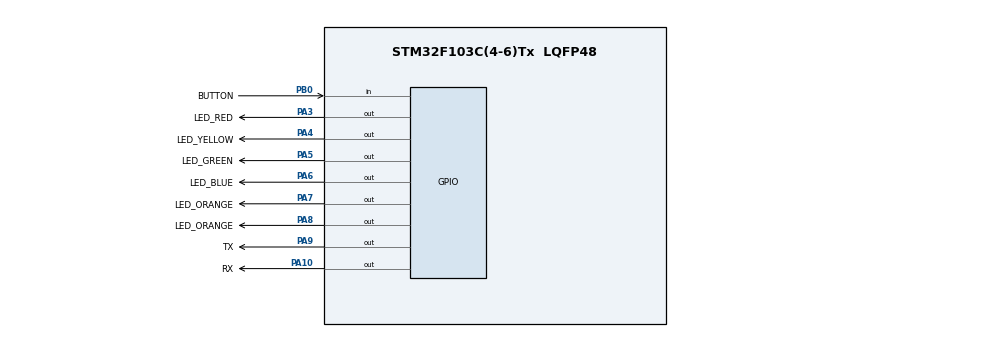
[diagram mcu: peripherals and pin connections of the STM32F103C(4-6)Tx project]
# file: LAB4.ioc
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Mcu.Family=STM32F1
Mcu.Name=STM32F103C(4-6)Tx
Mcu.Package=LQFP48
NVIC.PriorityGroup=NVIC_PRIORITYGROUP_4
NVIC.TIM2_IRQn=true\:0\:0\:false\:false\:true\:true\:true
PA10.GPIO_Label=RX
PA10.Signal=GPIO_Output
PA3.GPIO_Label=LED_RED
PA3.Signal=GPIO_Output
PA4.GPIO_Label=LED_YELLOW
PA4.Signal=GPIO_Output
PA5.GPIO_Label=LED_GREEN
PA5.Signal=GPIO_Output
PA6.GPIO_Label=LED_BLUE
PA6.Signal=GPIO_Output
PA7.GPIO_Label=LED_ORANGE
PA7.Signal=GPIO_Output
PA8.GPIO_Label=LED_ORANGE
PA8.Signal=GPIO_Output
PA9.GPIO_Label=TX
PA9.Signal=GPIO_Output
PB0.GPIO_Label=BUTTON
PB0.GPIO_PuPd=GPIO_PULLUP
PB0.Signal=GPIO_Input
ProjectManager.HeapSize=0x200
ProjectManager.StackSize=0x400
ProjectManager.TargetToolchain=STM32CubeIDE
RCC.APB1Freq_Value=8000000
RCC.APB2Freq_Value=8000000
TIM2.Period=9
TIM2.Prescaler=7999
VP_SYS_VS_ND.Mode=No_Debug
VP_TIM2_VS_ClockSourceINT.Mode=Internal
board=custom

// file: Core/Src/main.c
/* USER CODE BEGIN Header */
/**
  ******************************************************************************
  * @file           : main.c
  * @brief          : Main program body
  ******************************************************************************
  * @attention
  *
  * <h2><center>&copy; Copyright (c) 2023 STMicroelectronics.
  * All rights reserved.</center></h2>
  *
  * This software component is licensed by ST under BSD 3-Clause license,
  * the "License"; You may not use this file except in compliance with the
  * License. You may obtain a copy of the License at:
  *                        opensource.org/licenses/BSD-3-Clause
  *
  ******************************************************************************
  */
/* USER CODE END Header */
#include "main.h"

/* USER CODE BEGIN Includes */
#include "button.h"
#include "scheduler.h"
/* USER CODE END Includes */

TIM_HandleTypeDef htim2;

void SystemClock_Config(void);
static void MX_GPIO_Init(void);
static void MX_TIM2_Init(void);

/* USER CODE BEGIN 0 */
void ledred(){
	HAL_GPIO_TogglePin(LED_RED_GPIO_Port, LED_RED_Pin);
}

void ledyellow(){
	HAL_GPIO_TogglePin(LED_YELLOW_GPIO_Port, LED_YELLOW_Pin);
}

void ledgreen(){
	HAL_GPIO_TogglePin(LED_GREEN_GPIO_Port, LED_GREEN_Pin);
}

void ledblue(){
	HAL_GPIO_TogglePin(LED_BLUE_GPIO_Port, LED_BLUE_Pin);
}

void ledorange(){
	HAL_GPIO_TogglePin(LED_ORANGE_GPIO_Port, LED_ORANGE_Pin);
}

void ledone(){
	HAL_GPIO_TogglePin(LED_One_GPIO_Port, LED_One_Pin);
}

void ledbutton(){
	if (isButtonPressed(0)) {
		HAL_GPIO_TogglePin(LED_B_GPIO_Port, LED_B_Pin);
	}
}
/* USER CODE END 0 */

int main(void)
{

  /* MCU Configuration--------------------------------------------------------*/

  /* Reset of all peripherals, Initializes the Flash interface and the Systick. */
  HAL_Init();

  /* Configure the system clock */
  SystemClock_Config();

  /* Initialize all configured peripherals */
  MX_GPIO_Init();
  MX_TIM2_Init();
  /* USER CODE BEGIN 2 */
  HAL_TIM_Base_Start_IT (& htim2);
  SCH_Init();
  /* USER CODE END 2 */

  /* Infinite loop */
  /* USER CODE BEGIN WHILE */
  SCH_Add_Task(ledred, 500, 500);
  SCH_Add_Task(ledyellow, 1000, 1000);
  SCH_Add_Task(ledgreen, 1500, 1500);
  SCH_Add_Task(ledblue, 2000, 2000);
  SCH_Add_Task(ledorange, 2500, 2500);
  // One shot task
  SCH_Add_Task(ledone, 2000, 0);
  // Task with Button
  SCH_Add_Task(ledbutton, TIME_CYCLE, TIME_CYCLE);
  while (1)
  {
    /* USER CODE END WHILE */

    /* USER CODE BEGIN 3 */
	  SCH_Dispatch_Tasks();
  }
  /* USER CODE END 3 */
}

void SystemClock_Config(void)
{
  RCC_OscInitTypeDef RCC_OscInitStruct = {0};
  RCC_ClkInitTypeDef RCC_ClkInitStruct = {0};

  /** Initializes the RCC Oscillators according to the specified parameters
  * in the RCC_OscInitTypeDef structure.
  */
  RCC_OscInitStruct.OscillatorType = RCC_OSCILLATORTYPE_HSI;
  RCC_OscInitStruct.HSIState = RCC_HSI_ON;
  RCC_OscInitStruct.HSICalibrationValue = RCC_HSICALIBRATION_DEFAULT;
  RCC_OscInitStruct.PLL.PLLState = RCC_PLL_NONE;
  if (HAL_RCC_OscConfig(&RCC_OscInitStruct) != HAL_OK)
  {
    Error_Handler();
  }
  /** Initializes the CPU, AHB and APB buses clocks
  */
  RCC_ClkInitStruct.ClockType = RCC_CLOCKTYPE_HCLK|RCC_CLOCKTYPE_SYSCLK
                              |RCC_CLOCKTYPE_PCLK1|RCC_CLOCKTYPE_PCLK2;
  RCC_ClkInitStruct.SYSCLKSource = RCC_SYSCLKSOURCE_HSI;
  RCC_ClkInitStruct.AHBCLKDivider = RCC_SYSCLK_DIV1;
  RCC_ClkInitStruct.APB1CLKDivider = RCC_HCLK_DIV1;
  RCC_ClkInitStruct.APB2CLKDivider = RCC_HCLK_DIV1;

  if (HAL_RCC_ClockConfig(&RCC_ClkInitStruct, FLASH_LATENCY_0) != HAL_OK)
  {
    Error_Handler();
  }
}

static void MX_TIM2_Init(void)
{

  TIM_ClockConfigTypeDef sClockSourceConfig = {0};
  TIM_MasterConfigTypeDef sMasterConfig = {0};

  htim2.Instance = TIM2;
  htim2.Init.Prescaler = 7999;
  htim2.Init.CounterMode = TIM_COUNTERMODE_UP;
  htim2.Init.Period = 9;
  htim2.Init.ClockDivision = TIM_CLOCKDIVISION_DIV1;
  htim2.Init.AutoReloadPreload = TIM_AUTORELOAD_PRELOAD_DISABLE;
  if (HAL_TIM_Base_Init(&htim2) != HAL_OK)
  {
    Error_Handler();
  }
  sClockSourceConfig.ClockSource = TIM_CLOCKSOURCE_INTERNAL;
  if (HAL_TIM_ConfigClockSource(&htim2, &sClockSourceConfig) != HAL_OK)
  {
    Error_Handler();
  }
  sMasterConfig.MasterOutputTrigger = TIM_TRGO_RESET;
  sMasterConfig.MasterSlaveMode = TIM_MASTERSLAVEMODE_DISABLE;
  if (HAL_TIMEx_MasterConfigSynchronization(&htim2, &sMasterConfig) != HAL_OK)
  {
    Error_Handler();
  }
  /* USER CODE BEGIN TIM2_Init 2 */
  TIME_CYCLE = 1/(8e6/(htim2.Init.Prescaler + 1)/(htim2.Init.Period + 1)) * 1000; // Time cycle
  /* USER CODE END TIM2_Init 2 */

}

static void MX_GPIO_Init(void)
{
  GPIO_InitTypeDef GPIO_InitStruct = {0};

  /* GPIO Ports Clock Enable */
  __HAL_RCC_GPIOA_CLK_ENABLE();

  /*Configure GPIO pin Output Level */
  HAL_GPIO_WritePin(GPIOA, LED_RED_Pin|LED_YELLOW_Pin|LED_GREEN_Pin|LED_BLUE_Pin
                          |LED_ORANGE_Pin|LED_One_Pin|LED_B_Pin, GPIO_PIN_RESET);

  /*Configure GPIO pins : LED_RED_Pin LED_YELLOW_Pin LED_GREEN_Pin LED_BLUE_Pin
                           LED_ORANGE_Pin LED_One_Pin LED_B_Pin */
  GPIO_InitStruct.Pin = LED_RED_Pin|LED_YELLOW_Pin|LED_GREEN_Pin|LED_BLUE_Pin
                          |LED_ORANGE_Pin|LED_One_Pin|LED_B_Pin;
  GPIO_InitStruct.Mode = GPIO_MODE_OUTPUT_PP;
  GPIO_InitStruct.Pull = GPIO_NOPULL;
  GPIO_InitStruct.Speed = GPIO_SPEED_FREQ_LOW;
  HAL_GPIO_Init(GPIOA, &GPIO_InitStruct);

  /*Configure GPIO pin : BUTTON_Pin */
  GPIO_InitStruct.Pin = BUTTON_Pin;
  GPIO_InitStruct.Mode = GPIO_MODE_INPUT;
  GPIO_InitStruct.Pull = GPIO_PULLUP;
  HAL_GPIO_Init(BUTTON_GPIO_Port, &GPIO_InitStruct);

}

/* USER CODE BEGIN 4 */
void HAL_TIM_PeriodElapsedCallback(TIM_HandleTypeDef * htim){
	SCH_Update();
	getKeyInput();
}
/* USER CODE END 4 */

void Error_Handler(void)
{
  __disable_irq();
  while (1)
  {
  }
}

/************************ (C) COPYRIGHT STMicroelectronics *****END OF FILE****/
